VERSION 5.8 ;
BUSBITCHARS "[]" ;
DIVIDERCHAR "/" ;
UNITS
    DATABASE MICRONS 1000 ;
END UNITS

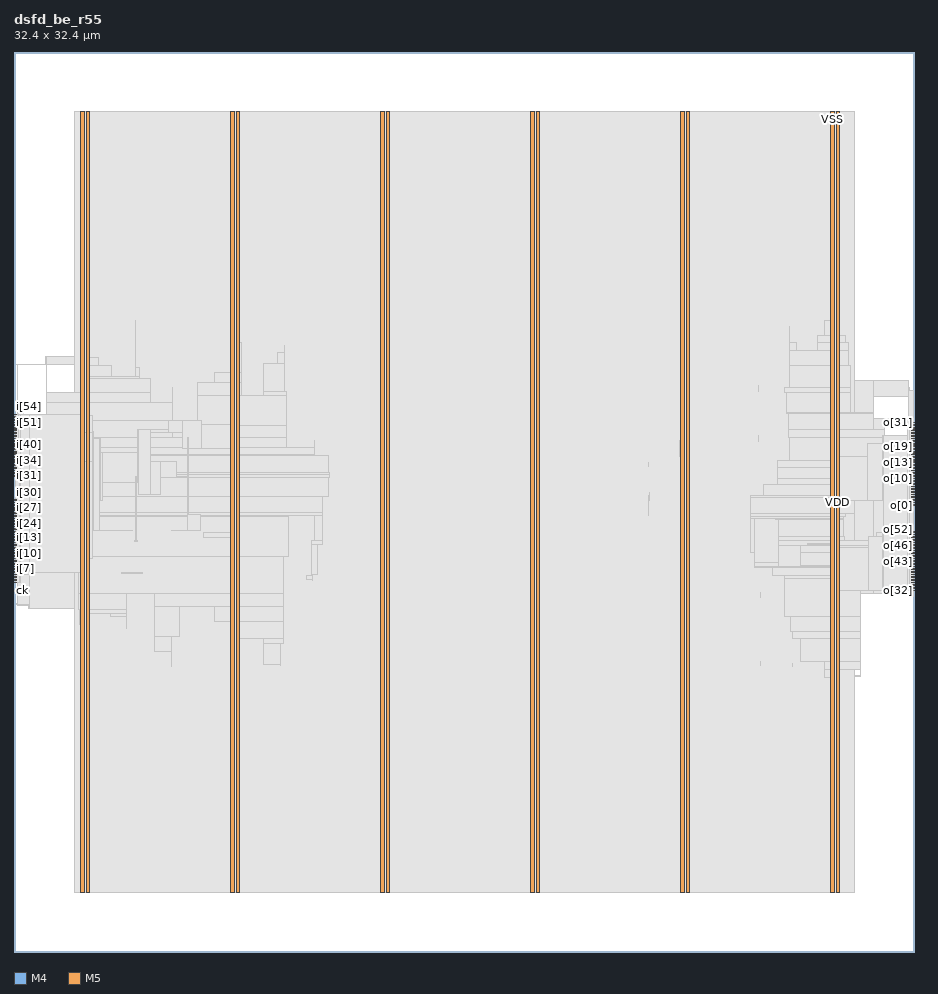
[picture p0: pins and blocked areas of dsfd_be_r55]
MACRO dsfd_be_r55
  FOREIGN dsfd_be_r55 0 0 ;
  CLASS BLOCK ;
  SIZE 32.4 BY 32.4 ;
  PIN ck
    DIRECTION INPUT ;
    USE SIGNAL ;
    PORT
      LAYER M4 ;
        RECT  0 13.296 0.084 13.32 ;
    END
  END ck
  PIN i[0]
    DIRECTION INPUT ;
    USE SIGNAL ;
    PORT
      LAYER M4 ;
        RECT  0 13.392 0.084 13.416 ;
    END
  END i[0]
  PIN i[10]
    DIRECTION INPUT ;
    USE SIGNAL ;
    PORT
      LAYER M4 ;
        RECT  0 14.352 0.084 14.376 ;
    END
  END i[10]
  PIN i[11]
    DIRECTION INPUT ;
    USE SIGNAL ;
    PORT
      LAYER M4 ;
        RECT  0 14.448 0.084 14.472 ;
    END
  END i[11]
  PIN i[12]
    DIRECTION INPUT ;
    USE SIGNAL ;
    PORT
      LAYER M4 ;
        RECT  0 14.544 0.084 14.568 ;
    END
  END i[12]
  PIN i[13]
    DIRECTION INPUT ;
    USE SIGNAL ;
    PORT
      LAYER M4 ;
        RECT  0 14.64 0.084 14.664 ;
    END
  END i[13]
  PIN i[14]
    DIRECTION INPUT ;
    USE SIGNAL ;
    PORT
      LAYER M4 ;
        RECT  0 14.736 0.084 14.76 ;
    END
  END i[14]
  PIN i[15]
    DIRECTION INPUT ;
    USE SIGNAL ;
    PORT
      LAYER M4 ;
        RECT  0 14.832 0.084 14.856 ;
    END
  END i[15]
  PIN i[16]
    DIRECTION INPUT ;
    USE SIGNAL ;
    PORT
      LAYER M4 ;
        RECT  0 14.928 0.084 14.952 ;
    END
  END i[16]
  PIN i[17]
    DIRECTION INPUT ;
    USE SIGNAL ;
    PORT
      LAYER M4 ;
        RECT  0 15.024 0.084 15.048 ;
    END
  END i[17]
  PIN i[18]
    DIRECTION INPUT ;
    USE SIGNAL ;
    PORT
      LAYER M4 ;
        RECT  0 15.12 0.084 15.144 ;
    END
  END i[18]
  PIN i[19]
    DIRECTION INPUT ;
    USE SIGNAL ;
    PORT
      LAYER M4 ;
        RECT  0 15.216 0.084 15.24 ;
    END
  END i[19]
  PIN i[1]
    DIRECTION INPUT ;
    USE SIGNAL ;
    PORT
      LAYER M4 ;
        RECT  0 13.488 0.084 13.512 ;
    END
  END i[1]
  PIN i[20]
    DIRECTION INPUT ;
    USE SIGNAL ;
    PORT
      LAYER M4 ;
        RECT  0 15.312 0.084 15.336 ;
    END
  END i[20]
  PIN i[21]
    DIRECTION INPUT ;
    USE SIGNAL ;
    PORT
      LAYER M4 ;
        RECT  0 15.408 0.084 15.432 ;
    END
  END i[21]
  PIN i[22]
    DIRECTION INPUT ;
    USE SIGNAL ;
    PORT
      LAYER M4 ;
        RECT  0 15.504 0.084 15.528 ;
    END
  END i[22]
  PIN i[23]
    DIRECTION INPUT ;
    USE SIGNAL ;
    PORT
      LAYER M4 ;
        RECT  0 15.6 0.084 15.624 ;
    END
  END i[23]
  PIN i[24]
    DIRECTION INPUT ;
    USE SIGNAL ;
    PORT
      LAYER M4 ;
        RECT  0 15.696 0.084 15.72 ;
    END
  END i[24]
  PIN i[25]
    DIRECTION INPUT ;
    USE SIGNAL ;
    PORT
      LAYER M4 ;
        RECT  0 15.792 0.084 15.816 ;
    END
  END i[25]
  PIN i[26]
    DIRECTION INPUT ;
    USE SIGNAL ;
    PORT
      LAYER M4 ;
        RECT  0 15.888 0.084 15.912 ;
    END
  END i[26]
  PIN i[27]
    DIRECTION INPUT ;
    USE SIGNAL ;
    PORT
      LAYER M4 ;
        RECT  0 15.984 0.084 16.008 ;
    END
  END i[27]
  PIN i[28]
    DIRECTION INPUT ;
    USE SIGNAL ;
    PORT
      LAYER M4 ;
        RECT  0 16.08 0.084 16.104 ;
    END
  END i[28]
  PIN i[29]
    DIRECTION INPUT ;
    USE SIGNAL ;
    PORT
      LAYER M4 ;
        RECT  0 16.176 0.084 16.2 ;
    END
  END i[29]
  PIN i[2]
    DIRECTION INPUT ;
    USE SIGNAL ;
    PORT
      LAYER M4 ;
        RECT  0 13.584 0.084 13.608 ;
    END
  END i[2]
  PIN i[30]
    DIRECTION INPUT ;
    USE SIGNAL ;
    PORT
      LAYER M4 ;
        RECT  0 16.272 0.084 16.296 ;
    END
  END i[30]
  PIN i[31]
    DIRECTION INPUT ;
    USE SIGNAL ;
    PORT
      LAYER M4 ;
        RECT  0 17.136 0.084 17.16 ;
    END
  END i[31]
  PIN i[32]
    DIRECTION INPUT ;
    USE SIGNAL ;
    PORT
      LAYER M4 ;
        RECT  0 17.232 0.084 17.256 ;
    END
  END i[32]
  PIN i[33]
    DIRECTION INPUT ;
    USE SIGNAL ;
    PORT
      LAYER M4 ;
        RECT  0 17.328 0.084 17.352 ;
    END
  END i[33]
  PIN i[34]
    DIRECTION INPUT ;
    USE SIGNAL ;
    PORT
      LAYER M4 ;
        RECT  0 17.424 0.084 17.448 ;
    END
  END i[34]
  PIN i[35]
    DIRECTION INPUT ;
    USE SIGNAL ;
    PORT
      LAYER M4 ;
        RECT  0 17.52 0.084 17.544 ;
    END
  END i[35]
  PIN i[36]
    DIRECTION INPUT ;
    USE SIGNAL ;
    PORT
      LAYER M4 ;
        RECT  0 17.616 0.084 17.64 ;
    END
  END i[36]
  PIN i[37]
    DIRECTION INPUT ;
    USE SIGNAL ;
    PORT
      LAYER M4 ;
        RECT  0 17.712 0.084 17.736 ;
    END
  END i[37]
  PIN i[38]
    DIRECTION INPUT ;
    USE SIGNAL ;
    PORT
      LAYER M4 ;
        RECT  0 17.808 0.084 17.832 ;
    END
  END i[38]
  PIN i[39]
    DIRECTION INPUT ;
    USE SIGNAL ;
    PORT
      LAYER M4 ;
        RECT  0 17.904 0.084 17.928 ;
    END
  END i[39]
  PIN i[3]
    DIRECTION INPUT ;
    USE SIGNAL ;
    PORT
      LAYER M4 ;
        RECT  0 13.68 0.084 13.704 ;
    END
  END i[3]
  PIN i[40]
    DIRECTION INPUT ;
    USE SIGNAL ;
    PORT
      LAYER M4 ;
        RECT  0 18 0.084 18.024 ;
    END
  END i[40]
  PIN i[41]
    DIRECTION INPUT ;
    USE SIGNAL ;
    PORT
      LAYER M4 ;
        RECT  0 18.096 0.084 18.12 ;
    END
  END i[41]
  PIN i[42]
    DIRECTION INPUT ;
    USE SIGNAL ;
    PORT
      LAYER M4 ;
        RECT  0 18.192 0.084 18.216 ;
    END
  END i[42]
  PIN i[43]
    DIRECTION INPUT ;
    USE SIGNAL ;
    PORT
      LAYER M4 ;
        RECT  0 18.288 0.084 18.312 ;
    END
  END i[43]
  PIN i[44]
    DIRECTION INPUT ;
    USE SIGNAL ;
    PORT
      LAYER M4 ;
        RECT  0 18.384 0.084 18.408 ;
    END
  END i[44]
  PIN i[45]
    DIRECTION INPUT ;
    USE SIGNAL ;
    PORT
      LAYER M4 ;
        RECT  0 18.48 0.084 18.504 ;
    END
  END i[45]
  PIN i[46]
    DIRECTION INPUT ;
    USE SIGNAL ;
    PORT
      LAYER M4 ;
        RECT  0 18.576 0.084 18.6 ;
    END
  END i[46]
  PIN i[47]
    DIRECTION INPUT ;
    USE SIGNAL ;
    PORT
      LAYER M4 ;
        RECT  0 18.672 0.084 18.696 ;
    END
  END i[47]
  PIN i[48]
    DIRECTION INPUT ;
    USE SIGNAL ;
    PORT
      LAYER M4 ;
        RECT  0 18.768 0.084 18.792 ;
    END
  END i[48]
  PIN i[49]
    DIRECTION INPUT ;
    USE SIGNAL ;
    PORT
      LAYER M4 ;
        RECT  0 18.864 0.084 18.888 ;
    END
  END i[49]
  PIN i[4]
    DIRECTION INPUT ;
    USE SIGNAL ;
    PORT
      LAYER M4 ;
        RECT  0 13.776 0.084 13.8 ;
    END
  END i[4]
  PIN i[50]
    DIRECTION INPUT ;
    USE SIGNAL ;
    PORT
      LAYER M4 ;
        RECT  0 18.96 0.084 18.984 ;
    END
  END i[50]
  PIN i[51]
    DIRECTION INPUT ;
    USE SIGNAL ;
    PORT
      LAYER M4 ;
        RECT  0 19.056 0.084 19.08 ;
    END
  END i[51]
  PIN i[52]
    DIRECTION INPUT ;
    USE SIGNAL ;
    PORT
      LAYER M4 ;
        RECT  0 19.152 0.084 19.176 ;
    END
  END i[52]
  PIN i[53]
    DIRECTION INPUT ;
    USE SIGNAL ;
    PORT
      LAYER M4 ;
        RECT  0 19.248 0.084 19.272 ;
    END
  END i[53]
  PIN i[54]
    DIRECTION INPUT ;
    USE SIGNAL ;
    PORT
      LAYER M4 ;
        RECT  0 19.344 0.084 19.368 ;
    END
  END i[54]
  PIN i[5]
    DIRECTION INPUT ;
    USE SIGNAL ;
    PORT
      LAYER M4 ;
        RECT  0 13.872 0.084 13.896 ;
    END
  END i[5]
  PIN i[6]
    DIRECTION INPUT ;
    USE SIGNAL ;
    PORT
      LAYER M4 ;
        RECT  0 13.968 0.084 13.992 ;
    END
  END i[6]
  PIN i[7]
    DIRECTION INPUT ;
    USE SIGNAL ;
    PORT
      LAYER M4 ;
        RECT  0 14.064 0.084 14.088 ;
    END
  END i[7]
  PIN i[8]
    DIRECTION INPUT ;
    USE SIGNAL ;
    PORT
      LAYER M4 ;
        RECT  0 14.16 0.084 14.184 ;
    END
  END i[8]
  PIN i[9]
    DIRECTION INPUT ;
    USE SIGNAL ;
    PORT
      LAYER M4 ;
        RECT  0 14.256 0.084 14.28 ;
    END
  END i[9]
  PIN o[0]
    DIRECTION OUTPUT ;
    USE SIGNAL ;
    PORT
      LAYER M4 ;
        RECT  32.316 16.08 32.4 16.104 ;
    END
  END o[0]
  PIN o[10]
    DIRECTION OUTPUT ;
    USE SIGNAL ;
    PORT
      LAYER M4 ;
        RECT  32.316 17.04 32.4 17.064 ;
    END
  END o[10]
  PIN o[11]
    DIRECTION OUTPUT ;
    USE SIGNAL ;
    PORT
      LAYER M4 ;
        RECT  32.316 17.136 32.4 17.16 ;
    END
  END o[11]
  PIN o[12]
    DIRECTION OUTPUT ;
    USE SIGNAL ;
    PORT
      LAYER M4 ;
        RECT  32.316 17.232 32.4 17.256 ;
    END
  END o[12]
  PIN o[13]
    DIRECTION OUTPUT ;
    USE SIGNAL ;
    PORT
      LAYER M4 ;
        RECT  32.316 17.328 32.4 17.352 ;
    END
  END o[13]
  PIN o[14]
    DIRECTION OUTPUT ;
    USE SIGNAL ;
    PORT
      LAYER M4 ;
        RECT  32.316 17.424 32.4 17.448 ;
    END
  END o[14]
  PIN o[15]
    DIRECTION OUTPUT ;
    USE SIGNAL ;
    PORT
      LAYER M4 ;
        RECT  32.316 17.52 32.4 17.544 ;
    END
  END o[15]
  PIN o[16]
    DIRECTION OUTPUT ;
    USE SIGNAL ;
    PORT
      LAYER M4 ;
        RECT  32.316 17.616 32.4 17.64 ;
    END
  END o[16]
  PIN o[17]
    DIRECTION OUTPUT ;
    USE SIGNAL ;
    PORT
      LAYER M4 ;
        RECT  32.316 17.712 32.4 17.736 ;
    END
  END o[17]
  PIN o[18]
    DIRECTION OUTPUT ;
    USE SIGNAL ;
    PORT
      LAYER M4 ;
        RECT  32.316 17.808 32.4 17.832 ;
    END
  END o[18]
  PIN o[19]
    DIRECTION OUTPUT ;
    USE SIGNAL ;
    PORT
      LAYER M4 ;
        RECT  32.316 17.904 32.4 17.928 ;
    END
  END o[19]
  PIN o[1]
    DIRECTION OUTPUT ;
    USE SIGNAL ;
    PORT
      LAYER M4 ;
        RECT  32.316 16.176 32.4 16.2 ;
    END
  END o[1]
  PIN o[20]
    DIRECTION OUTPUT ;
    USE SIGNAL ;
    PORT
      LAYER M4 ;
        RECT  32.316 18 32.4 18.024 ;
    END
  END o[20]
  PIN o[21]
    DIRECTION OUTPUT ;
    USE SIGNAL ;
    PORT
      LAYER M4 ;
        RECT  32.316 18.096 32.4 18.12 ;
    END
  END o[21]
  PIN o[22]
    DIRECTION OUTPUT ;
    USE SIGNAL ;
    PORT
      LAYER M4 ;
        RECT  32.316 18.192 32.4 18.216 ;
    END
  END o[22]
  PIN o[23]
    DIRECTION OUTPUT ;
    USE SIGNAL ;
    PORT
      LAYER M4 ;
        RECT  32.316 18.288 32.4 18.312 ;
    END
  END o[23]
  PIN o[24]
    DIRECTION OUTPUT ;
    USE SIGNAL ;
    PORT
      LAYER M4 ;
        RECT  32.316 18.384 32.4 18.408 ;
    END
  END o[24]
  PIN o[25]
    DIRECTION OUTPUT ;
    USE SIGNAL ;
    PORT
      LAYER M4 ;
        RECT  32.316 18.48 32.4 18.504 ;
    END
  END o[25]
  PIN o[26]
    DIRECTION OUTPUT ;
    USE SIGNAL ;
    PORT
      LAYER M4 ;
        RECT  32.316 18.576 32.4 18.6 ;
    END
  END o[26]
  PIN o[27]
    DIRECTION OUTPUT ;
    USE SIGNAL ;
    PORT
      LAYER M4 ;
        RECT  32.316 18.672 32.4 18.696 ;
    END
  END o[27]
  PIN o[28]
    DIRECTION OUTPUT ;
    USE SIGNAL ;
    PORT
      LAYER M4 ;
        RECT  32.316 18.768 32.4 18.792 ;
    END
  END o[28]
  PIN o[29]
    DIRECTION OUTPUT ;
    USE SIGNAL ;
    PORT
      LAYER M4 ;
        RECT  32.316 18.864 32.4 18.888 ;
    END
  END o[29]
  PIN o[2]
    DIRECTION OUTPUT ;
    USE SIGNAL ;
    PORT
      LAYER M4 ;
        RECT  32.316 16.272 32.4 16.296 ;
    END
  END o[2]
  PIN o[30]
    DIRECTION OUTPUT ;
    USE SIGNAL ;
    PORT
      LAYER M4 ;
        RECT  32.316 18.96 32.4 18.984 ;
    END
  END o[30]
  PIN o[31]
    DIRECTION OUTPUT ;
    USE SIGNAL ;
    PORT
      LAYER M4 ;
        RECT  32.316 19.056 32.4 19.08 ;
    END
  END o[31]
  PIN o[32]
    DIRECTION OUTPUT ;
    USE SIGNAL ;
    PORT
      LAYER M4 ;
        RECT  32.316 13.008 32.4 13.032 ;
    END
  END o[32]
  PIN o[33]
    DIRECTION OUTPUT ;
    USE SIGNAL ;
    PORT
      LAYER M4 ;
        RECT  32.316 13.104 32.4 13.128 ;
    END
  END o[33]
  PIN o[34]
    DIRECTION OUTPUT ;
    USE SIGNAL ;
    PORT
      LAYER M4 ;
        RECT  32.316 13.2 32.4 13.224 ;
    END
  END o[34]
  PIN o[35]
    DIRECTION OUTPUT ;
    USE SIGNAL ;
    PORT
      LAYER M4 ;
        RECT  32.316 13.296 32.4 13.32 ;
    END
  END o[35]
  PIN o[36]
    DIRECTION OUTPUT ;
    USE SIGNAL ;
    PORT
      LAYER M4 ;
        RECT  32.316 13.392 32.4 13.416 ;
    END
  END o[36]
  PIN o[37]
    DIRECTION OUTPUT ;
    USE SIGNAL ;
    PORT
      LAYER M4 ;
        RECT  32.316 13.488 32.4 13.512 ;
    END
  END o[37]
  PIN o[38]
    DIRECTION OUTPUT ;
    USE SIGNAL ;
    PORT
      LAYER M4 ;
        RECT  32.316 13.584 32.4 13.608 ;
    END
  END o[38]
  PIN o[39]
    DIRECTION OUTPUT ;
    USE SIGNAL ;
    PORT
      LAYER M4 ;
        RECT  32.316 13.68 32.4 13.704 ;
    END
  END o[39]
  PIN o[3]
    DIRECTION OUTPUT ;
    USE SIGNAL ;
    PORT
      LAYER M4 ;
        RECT  32.316 16.368 32.4 16.392 ;
    END
  END o[3]
  PIN o[40]
    DIRECTION OUTPUT ;
    USE SIGNAL ;
    PORT
      LAYER M4 ;
        RECT  32.316 13.776 32.4 13.8 ;
    END
  END o[40]
  PIN o[41]
    DIRECTION OUTPUT ;
    USE SIGNAL ;
    PORT
      LAYER M4 ;
        RECT  32.316 13.872 32.4 13.896 ;
    END
  END o[41]
  PIN o[42]
    DIRECTION OUTPUT ;
    USE SIGNAL ;
    PORT
      LAYER M4 ;
        RECT  32.316 13.968 32.4 13.992 ;
    END
  END o[42]
  PIN o[43]
    DIRECTION OUTPUT ;
    USE SIGNAL ;
    PORT
      LAYER M4 ;
        RECT  32.316 14.064 32.4 14.088 ;
    END
  END o[43]
  PIN o[44]
    DIRECTION OUTPUT ;
    USE SIGNAL ;
    PORT
      LAYER M4 ;
        RECT  32.316 14.16 32.4 14.184 ;
    END
  END o[44]
  PIN o[45]
    DIRECTION OUTPUT ;
    USE SIGNAL ;
    PORT
      LAYER M4 ;
        RECT  32.316 14.256 32.4 14.28 ;
    END
  END o[45]
  PIN o[46]
    DIRECTION OUTPUT ;
    USE SIGNAL ;
    PORT
      LAYER M4 ;
        RECT  32.316 14.352 32.4 14.376 ;
    END
  END o[46]
  PIN o[47]
    DIRECTION OUTPUT ;
    USE SIGNAL ;
    PORT
      LAYER M4 ;
        RECT  32.316 14.448 32.4 14.472 ;
    END
  END o[47]
  PIN o[48]
    DIRECTION OUTPUT ;
    USE SIGNAL ;
    PORT
      LAYER M4 ;
        RECT  32.316 14.544 32.4 14.568 ;
    END
  END o[48]
  PIN o[49]
    DIRECTION OUTPUT ;
    USE SIGNAL ;
    PORT
      LAYER M4 ;
        RECT  32.316 14.64 32.4 14.664 ;
    END
  END o[49]
  PIN o[4]
    DIRECTION OUTPUT ;
    USE SIGNAL ;
    PORT
      LAYER M4 ;
        RECT  32.316 16.464 32.4 16.488 ;
    END
  END o[4]
  PIN o[50]
    DIRECTION OUTPUT ;
    USE SIGNAL ;
    PORT
      LAYER M4 ;
        RECT  32.316 14.736 32.4 14.76 ;
    END
  END o[50]
  PIN o[51]
    DIRECTION OUTPUT ;
    USE SIGNAL ;
    PORT
      LAYER M4 ;
        RECT  32.316 14.832 32.4 14.856 ;
    END
  END o[51]
  PIN o[52]
    DIRECTION OUTPUT ;
    USE SIGNAL ;
    PORT
      LAYER M4 ;
        RECT  32.316 14.928 32.4 14.952 ;
    END
  END o[52]
  PIN o[53]
    DIRECTION OUTPUT ;
    USE SIGNAL ;
    PORT
      LAYER M4 ;
        RECT  32.316 15.024 32.4 15.048 ;
    END
  END o[53]
  PIN o[54]
    DIRECTION OUTPUT ;
    USE SIGNAL ;
    PORT
      LAYER M4 ;
        RECT  32.316 15.12 32.4 15.144 ;
    END
  END o[54]
  PIN o[5]
    DIRECTION OUTPUT ;
    USE SIGNAL ;
    PORT
      LAYER M4 ;
        RECT  32.316 16.56 32.4 16.584 ;
    END
  END o[5]
  PIN o[6]
    DIRECTION OUTPUT ;
    USE SIGNAL ;
    PORT
      LAYER M4 ;
        RECT  32.316 16.656 32.4 16.68 ;
    END
  END o[6]
  PIN o[7]
    DIRECTION OUTPUT ;
    USE SIGNAL ;
    PORT
      LAYER M4 ;
        RECT  32.316 16.752 32.4 16.776 ;
    END
  END o[7]
  PIN o[8]
    DIRECTION OUTPUT ;
    USE SIGNAL ;
    PORT
      LAYER M4 ;
        RECT  32.316 16.848 32.4 16.872 ;
    END
  END o[8]
  PIN o[9]
    DIRECTION OUTPUT ;
    USE SIGNAL ;
    PORT
      LAYER M4 ;
        RECT  32.316 16.944 32.4 16.968 ;
    END
  END o[9]
  PIN VDD
    DIRECTION INOUT ;
    USE POWER ;
    PORT
      LAYER M5 ;
        RECT  29.592 2.151 29.712 30.249 ;
        RECT  24.192 2.151 24.312 30.249 ;
        RECT  18.792 2.151 18.912 30.249 ;
        RECT  13.392 2.151 13.512 30.249 ;
        RECT  7.992 2.151 8.112 30.249 ;
        RECT  2.592 2.151 2.712 30.249 ;
    END
  END VDD
  PIN VSS
    DIRECTION INOUT ;
    USE GROUND ;
    PORT
      LAYER M5 ;
        RECT  29.4 2.137 29.52 30.263 ;
        RECT  24 2.137 24.12 30.263 ;
        RECT  18.6 2.137 18.72 30.263 ;
        RECT  13.2 2.137 13.32 30.263 ;
        RECT  7.8 2.137 7.92 30.263 ;
        RECT  2.4 2.137 2.52 30.263 ;
    END
  END VSS
  # OT_OBS_CLOSED layer=M5 d_um=1.536 added=0
  OBS
    LAYER RVTN ;
     RECT  2.16 2.16 30.24 2.295 ;
     RECT  2.16 2.565 30.24 2.835 ;
     RECT  2.16 3.105 30.24 3.375 ;
     RECT  2.16 3.645 30.24 3.915 ;
     RECT  2.16 4.185 30.24 4.455 ;
     RECT  2.16 4.725 30.24 4.995 ;
     RECT  2.16 5.265 30.24 5.535 ;
     RECT  2.16 5.805 30.24 6.075 ;
     RECT  2.16 6.345 30.24 6.615 ;
     RECT  2.16 6.885 30.24 7.155 ;
     RECT  2.16 7.425 30.24 7.695 ;
     RECT  2.16 7.965 30.24 8.235 ;
     RECT  2.16 8.505 30.24 8.775 ;
     RECT  2.16 9.045 30.24 9.315 ;
     RECT  2.16 9.585 30.24 9.855 ;
     RECT  2.16 10.125 30.24 10.395 ;
     RECT  2.16 10.665 30.24 10.935 ;
     RECT  2.16 11.205 30.24 11.475 ;
     RECT  2.16 11.745 30.24 12.015 ;
     RECT  2.16 12.285 30.24 12.555 ;
     RECT  2.16 12.825 30.24 13.095 ;
     RECT  2.16 13.365 30.24 13.635 ;
     RECT  2.16 13.905 30.24 14.175 ;
     RECT  2.16 14.445 30.24 14.715 ;
     RECT  2.16 14.985 30.24 15.255 ;
     RECT  2.16 15.525 30.24 15.795 ;
     RECT  2.16 16.065 30.24 16.335 ;
     RECT  2.16 16.605 30.24 16.875 ;
     RECT  2.16 17.145 30.24 17.415 ;
     RECT  2.16 17.685 30.24 17.955 ;
     RECT  2.16 18.225 30.24 18.495 ;
     RECT  2.16 18.765 30.24 19.035 ;
     RECT  2.16 19.305 30.24 19.575 ;
     RECT  2.16 19.845 30.24 20.115 ;
     RECT  2.16 20.385 30.24 20.655 ;
     RECT  2.16 20.925 30.24 21.195 ;
     RECT  2.16 21.465 30.24 21.735 ;
     RECT  2.16 22.005 30.24 22.275 ;
     RECT  2.16 22.545 30.24 22.815 ;
     RECT  2.16 23.085 30.24 23.355 ;
     RECT  2.16 23.625 30.24 23.895 ;
     RECT  2.16 24.165 30.24 24.435 ;
     RECT  2.16 24.705 30.24 24.975 ;
     RECT  2.16 25.245 30.24 25.515 ;
     RECT  2.16 25.785 30.24 26.055 ;
     RECT  2.16 26.325 30.24 26.595 ;
     RECT  2.16 26.865 30.24 27.135 ;
     RECT  2.16 27.405 30.24 27.675 ;
     RECT  2.16 27.945 30.24 28.215 ;
     RECT  2.16 28.485 30.24 28.755 ;
     RECT  2.16 29.025 30.24 29.295 ;
     RECT  2.16 29.565 30.24 29.835 ;
     RECT  2.16 30.105 30.24 30.24 ;
    LAYER RVTP ;
     RECT  2.16 2.295 30.24 2.565 ;
     RECT  2.16 2.835 30.24 3.105 ;
     RECT  2.16 3.375 30.24 3.645 ;
     RECT  2.16 3.915 30.24 4.185 ;
     RECT  2.16 4.455 30.24 4.725 ;
     RECT  2.16 4.995 30.24 5.265 ;
     RECT  2.16 5.535 30.24 5.805 ;
     RECT  2.16 6.075 30.24 6.345 ;
     RECT  2.16 6.615 30.24 6.885 ;
     RECT  2.16 7.155 30.24 7.425 ;
     RECT  2.16 7.695 30.24 7.965 ;
     RECT  2.16 8.235 30.24 8.505 ;
     RECT  2.16 8.775 30.24 9.045 ;
     RECT  2.16 9.315 30.24 9.585 ;
     RECT  2.16 9.855 30.24 10.125 ;
     RECT  2.16 10.395 30.24 10.665 ;
     RECT  2.16 10.935 30.24 11.205 ;
     RECT  2.16 11.475 30.24 11.745 ;
     RECT  2.16 12.015 30.24 12.285 ;
     RECT  2.16 12.555 30.24 12.825 ;
     RECT  2.16 13.095 30.24 13.365 ;
     RECT  2.16 13.635 30.24 13.905 ;
     RECT  2.16 14.175 30.24 14.445 ;
     RECT  2.16 14.715 30.24 14.985 ;
     RECT  2.16 15.255 30.24 15.525 ;
     RECT  2.16 15.795 30.24 16.065 ;
     RECT  2.16 16.335 30.24 16.605 ;
     RECT  2.16 16.875 30.24 17.145 ;
     RECT  2.16 17.415 30.24 17.685 ;
     RECT  2.16 17.955 30.24 18.225 ;
     RECT  2.16 18.495 30.24 18.765 ;
     RECT  2.16 19.035 30.24 19.305 ;
     RECT  2.16 19.575 30.24 19.845 ;
     RECT  2.16 20.115 30.24 20.385 ;
     RECT  2.16 20.655 30.24 20.925 ;
     RECT  2.16 21.195 30.24 21.465 ;
     RECT  2.16 21.735 30.24 22.005 ;
     RECT  2.16 22.275 30.24 22.545 ;
     RECT  2.16 22.815 30.24 23.085 ;
     RECT  2.16 23.355 30.24 23.625 ;
     RECT  2.16 23.895 30.24 24.165 ;
     RECT  2.16 24.435 30.24 24.705 ;
     RECT  2.16 24.975 30.24 25.245 ;
     RECT  2.16 25.515 30.24 25.785 ;
     RECT  2.16 26.055 30.24 26.325 ;
     RECT  2.16 26.595 30.24 26.865 ;
     RECT  2.16 27.135 30.24 27.405 ;
     RECT  2.16 27.675 30.24 27.945 ;
     RECT  2.16 28.215 30.24 28.485 ;
     RECT  2.16 28.755 30.24 29.025 ;
     RECT  2.16 29.295 30.24 29.565 ;
     RECT  2.16 29.835 30.24 30.105 ;
    LAYER M1 ;
     RECT  2.16 2.151 30.24 30.249 ;
    LAYER M2 ;
     RECT  0.103 12.528 0.139 12.546 ;
     RECT  0.103 13.572 0.139 13.59 ;
     RECT  0.139 12.492 0.175 12.546 ;
     RECT  0.139 13.572 0.175 13.662 ;
     RECT  0.103 14.571 0.175 14.778 ;
     RECT  0.175 12.492 0.535 14.778 ;
     RECT  0.103 21.132 1.147 21.15 ;
     RECT  0.535 12.366 2.16 14.778 ;
     RECT  0.175 16.11 2.16 16.128 ;
     RECT  0.535 16.956 2.16 16.974 ;
     RECT  1.687 20.124 2.16 20.142 ;
     RECT  1.147 21.132 2.16 21.42 ;
     RECT  2.16 2.151 30.24 30.249 ;
     RECT  30.24 9.936 30.479 9.954 ;
     RECT  30.24 12.906 30.947 20.574 ;
     RECT  30.947 12.906 31.343 19.224 ;
     RECT  31.343 12.906 31.379 13.932 ;
     RECT  31.343 15.876 31.379 15.894 ;
     RECT  31.379 13.914 31.415 13.932 ;
     RECT  30.947 20.016 32.207 20.574 ;
     RECT  32.207 20.016 32.243 20.304 ;
     RECT  31.343 18.936 32.279 19.224 ;
     RECT  31.343 14.724 32.315 14.742 ;
     RECT  31.343 16.848 32.315 17.514 ;
     RECT  32.243 20.016 32.315 20.214 ;
     RECT  32.287 18.396 32.387 18.414 ;
     RECT  32.315 20.196 32.387 20.214 ;
    LAYER M3 ;
     RECT  2.415 2.143 2.505 2.413 ;
     RECT  7.815 2.143 7.905 2.413 ;
     RECT  13.215 2.143 13.305 2.413 ;
     RECT  18.615 2.143 18.705 2.413 ;
     RECT  24.015 2.143 24.105 2.413 ;
     RECT  29.415 2.143 29.505 2.413 ;
     RECT  29.415 2.413 29.697 9.895 ;
     RECT  29.16 9.895 29.697 10.165 ;
     RECT  30.456 9.931 30.474 10.165 ;
     RECT  9.576 10.327 9.594 10.363 ;
     RECT  28.008 10.291 28.026 10.391 ;
     RECT  26.856 10.327 26.874 10.463 ;
     RECT  29.16 10.165 30.474 10.471 ;
     RECT  5.652 10.291 5.67 10.831 ;
     RECT  8.964 10.363 9.594 11.101 ;
     RECT  7.815 2.413 8.097 11.281 ;
     RECT  8.964 11.101 9.702 11.281 ;
     RECT  28.296 10.471 30.474 11.281 ;
     RECT  5.04 10.831 5.67 11.371 ;
     RECT  28.008 11.281 30.474 11.551 ;
     RECT  2.415 2.413 2.697 11.785 ;
     RECT  7.815 11.281 9.702 11.911 ;
     RECT  4.032 11.641 4.05 12.091 ;
     RECT  27.936 11.551 30.474 12.091 ;
     RECT  2.34 11.785 2.697 12.181 ;
     RECT  3.456 12.091 4.05 12.181 ;
     RECT  2.34 12.181 4.05 12.325 ;
     RECT  5.04 11.371 5.958 12.451 ;
     RECT  7.2 11.911 9.702 12.451 ;
     RECT  0.54 12.361 0.558 12.487 ;
     RECT  0.144 12.487 0.558 12.523 ;
     RECT  2.304 12.325 4.05 12.901 ;
     RECT  5.04 12.451 9.702 12.901 ;
     RECT  26.856 12.757 26.874 12.929 ;
     RECT  10.728 13.369 10.746 13.405 ;
     RECT  27.72 12.091 30.474 13.441 ;
     RECT  31.356 12.901 31.374 13.441 ;
     RECT  10.512 13.405 10.746 13.559 ;
     RECT  27.72 13.441 31.374 13.567 ;
     RECT  10.692 13.559 10.746 13.603 ;
     RECT  0.108 12.523 0.558 13.613 ;
     RECT  27.288 13.567 31.374 13.837 ;
     RECT  26.64 13.837 31.374 13.865 ;
     RECT  28.296 13.865 31.374 13.9 ;
     RECT  26.64 13.865 27.522 14.009 ;
     RECT  2.304 12.901 9.702 14.251 ;
     RECT  26.64 14.009 26.658 14.377 ;
     RECT  28.296 13.9 31.41 14.381 ;
     RECT  27.504 14.009 27.522 14.647 ;
     RECT  28.296 14.381 31.338 14.647 ;
     RECT  0.108 13.613 0.342 14.669 ;
     RECT  10.692 13.603 10.926 14.683 ;
     RECT  10.692 14.683 11.106 14.819 ;
     RECT  27.504 14.647 31.338 14.819 ;
     RECT  32.292 14.719 32.31 14.861 ;
     RECT  27.504 14.819 29.898 14.945 ;
     RECT  0.108 14.669 0.306 14.957 ;
     RECT  30.78 14.819 31.338 14.957 ;
     RECT  31.032 14.957 31.338 15.089 ;
     RECT  31.284 15.089 31.338 15.179 ;
     RECT  0.144 14.957 0.306 15.341 ;
     RECT  27.504 14.945 29.862 15.565 ;
     RECT  26.496 14.377 26.658 15.601 ;
     RECT  27.396 15.565 29.862 15.601 ;
     RECT  2.304 14.251 9.882 15.691 ;
     RECT  26.496 15.601 29.862 15.691 ;
     RECT  2.268 15.691 9.882 15.727 ;
     RECT  10.8 14.819 11.106 15.727 ;
     RECT  26.496 15.691 29.934 15.799 ;
     RECT  2.268 15.727 11.106 15.827 ;
     RECT  31.32 15.179 31.338 15.871 ;
     RECT  0.144 15.341 0.162 16.105 ;
     RECT  0.144 16.105 0.198 16.171 ;
     RECT  31.32 15.871 31.374 16.205 ;
     RECT  0.144 16.171 0.342 16.267 ;
     RECT  22.824 15.727 22.842 16.267 ;
     RECT  26.496 15.799 30.258 16.363 ;
     RECT  31.32 16.205 31.338 16.363 ;
     RECT  0.108 16.267 0.342 16.397 ;
     RECT  2.304 15.827 11.106 16.411 ;
     RECT  22.824 16.267 22.878 16.439 ;
     RECT  26.496 16.363 31.338 16.439 ;
     RECT  22.86 16.439 22.878 16.529 ;
     RECT  26.964 16.439 31.338 16.835 ;
     RECT  0.18 16.397 0.342 16.951 ;
     RECT  27.468 16.835 31.338 17.041 ;
     RECT  2.304 16.411 11.322 17.077 ;
     RECT  0.18 16.951 0.558 17.165 ;
     RECT  2.304 17.077 11.358 17.185 ;
     RECT  2.268 17.185 11.358 17.249 ;
     RECT  0.54 17.165 0.558 17.261 ;
     RECT  27.468 17.041 31.374 17.453 ;
     RECT  32.292 16.747 32.31 17.519 ;
     RECT  22.824 17.491 22.842 17.609 ;
     RECT  27.468 17.453 31.338 17.681 ;
     RECT  24.015 2.413 24.297 17.851 ;
     RECT  2.268 17.249 11.322 17.879 ;
     RECT  2.268 17.879 10.818 17.899 ;
     RECT  1.692 17.899 10.818 18.149 ;
     RECT  0.432 18.283 0.45 18.379 ;
     RECT  32.292 18.379 32.31 18.391 ;
     RECT  10.8 18.149 10.818 18.419 ;
     RECT  23.94 17.851 24.297 18.419 ;
     RECT  0.36 18.379 0.45 18.461 ;
     RECT  0.36 18.461 0.378 18.509 ;
     RECT  1.692 18.149 9.81 18.527 ;
     RECT  27.9 17.681 31.338 18.535 ;
     RECT  26.784 18.391 26.802 18.599 ;
     RECT  32.292 18.391 32.382 18.763 ;
     RECT  27.864 18.535 31.338 18.797 ;
     RECT  32.256 18.763 32.382 18.859 ;
     RECT  32.22 18.859 32.382 18.955 ;
     RECT  6.552 18.527 9.81 18.959 ;
     RECT  1.692 18.527 5.706 19.147 ;
     RECT  0.108 18.763 0.342 19.373 ;
     RECT  27.864 18.797 30.942 19.381 ;
     RECT  27.792 19.381 30.942 19.409 ;
     RECT  30.924 19.409 30.942 19.679 ;
     RECT  1.152 19.147 5.706 19.769 ;
     RECT  6.588 18.959 9.81 20.039 ;
     RECT  1.152 19.769 4.914 20.147 ;
     RECT  27.792 19.409 30.114 20.155 ;
     RECT  8.964 20.039 9.81 20.183 ;
     RECT  32.184 18.955 32.382 20.219 ;
     RECT  5.688 19.769 5.706 20.309 ;
     RECT  27.72 20.155 30.114 20.309 ;
     RECT  32.184 20.219 32.238 20.309 ;
     RECT  26.784 20.191 26.802 20.381 ;
     RECT  6.588 20.039 8.19 20.489 ;
     RECT  32.184 20.309 32.202 20.579 ;
     RECT  2.415 20.147 4.914 20.651 ;
     RECT  2.415 20.651 4.518 20.723 ;
     RECT  7.2 20.489 8.19 20.849 ;
     RECT  4.356 20.723 4.518 21.029 ;
     RECT  2.415 20.723 3.51 21.119 ;
     RECT  27.9 20.309 30.114 21.119 ;
     RECT  0.108 19.373 0.126 21.155 ;
     RECT  8.964 20.183 9.738 21.191 ;
     RECT  2.415 21.119 3.042 21.389 ;
     RECT  1.152 20.147 1.17 21.425 ;
     RECT  9.468 21.191 9.738 21.569 ;
     RECT  27.9 21.119 30.042 21.659 ;
     RECT  9.72 21.569 9.738 21.839 ;
     RECT  7.815 20.849 8.19 21.929 ;
     RECT  27.9 21.659 28.17 21.929 ;
     RECT  28.908 21.659 30.042 21.929 ;
     RECT  28.908 21.929 29.934 22.199 ;
     RECT  27.9 21.929 27.918 22.505 ;
     RECT  4.356 21.029 4.374 22.739 ;
     RECT  29.16 22.199 29.697 22.739 ;
     RECT  2.415 21.389 2.697 29.987 ;
     RECT  7.815 21.929 8.097 29.987 ;
     RECT  13.215 2.413 13.497 29.987 ;
     RECT  18.615 2.413 18.897 29.987 ;
     RECT  24.015 18.419 24.297 29.987 ;
     RECT  29.415 22.739 29.697 29.987 ;
     RECT  2.415 29.987 2.505 30.257 ;
     RECT  7.815 29.987 7.905 30.257 ;
     RECT  13.215 29.987 13.305 30.257 ;
     RECT  18.615 29.987 18.705 30.257 ;
     RECT  24.015 29.987 24.105 30.257 ;
     RECT  29.415 29.987 29.505 30.257 ;
    LAYER M4 ;
     RECT  0.06 13.296 0.227 19.368 ;
     RECT  0.227 13.584 0.569 19.368 ;
     RECT  0.569 13.68 2.408 19.368 ;
     RECT  2.408 2.148 2.512 30.252 ;
     RECT  2.512 2.418 2.704 29.982 ;
     RECT  2.704 14.16 2.837 19.32 ;
     RECT  2.837 15.168 2.873 18.744 ;
     RECT  2.873 15.168 3.089 18.504 ;
     RECT  3.089 16.272 3.125 18.504 ;
     RECT  3.125 16.272 3.197 17.976 ;
     RECT  3.089 15.168 4.277 15.192 ;
     RECT  4.345 14.784 4.429 14.808 ;
     RECT  3.197 16.896 4.453 17.976 ;
     RECT  4.453 16.896 4.489 18.792 ;
     RECT  3.877 13.632 4.637 13.656 ;
     RECT  4.489 16.464 4.925 18.792 ;
     RECT  4.925 16.464 5.285 17.64 ;
     RECT  4.925 18.72 5.569 18.792 ;
     RECT  5.285 17.088 5.861 17.64 ;
     RECT  5.569 18.72 6.073 19.128 ;
     RECT  5.677 15.168 6.229 15.192 ;
     RECT  5.861 17.088 6.275 17.112 ;
     RECT  6.229 15.168 6.725 15.768 ;
     RECT  6.073 18.144 6.761 19.128 ;
     RECT  6.829 14.928 7.808 15.096 ;
     RECT  6.761 18.144 7.808 18.984 ;
     RECT  7.808 2.148 7.912 30.252 ;
     RECT  7.912 2.418 8.104 29.982 ;
     RECT  13.208 2.148 13.312 30.252 ;
     RECT  13.312 2.418 13.504 29.982 ;
     RECT  18.608 2.148 18.712 30.252 ;
     RECT  18.712 2.418 18.904 29.982 ;
     RECT  24.008 2.148 24.112 30.252 ;
     RECT  24.112 2.418 24.304 29.982 ;
     RECT  28.573 14.688 29.408 14.712 ;
     RECT  29.408 2.148 29.512 30.252 ;
     RECT  29.512 2.418 29.704 29.982 ;
     RECT  29.704 16.272 30.733 17.832 ;
     RECT  29.704 13.008 30.769 14.568 ;
     RECT  30.769 13.008 31.273 14.952 ;
     RECT  30.733 16.272 31.273 18.312 ;
     RECT  31.273 13.008 31.309 15.144 ;
     RECT  31.273 16.272 31.309 18.6 ;
     RECT  31.309 13.008 32.173 18.6 ;
     RECT  32.173 13.008 32.245 18.984 ;
     RECT  32.245 13.008 32.364 19.08 ;
    LAYER M5 ;
     RECT  2.4 2.137 2.52 2.151 ;
     RECT  7.8 2.137 7.92 2.151 ;
     RECT  13.2 2.137 13.32 2.151 ;
     RECT  18.6 2.137 18.72 2.151 ;
     RECT  24 2.137 24.12 2.151 ;
     RECT  29.4 2.137 29.52 2.151 ;
     RECT  0.192 13.285 0.216 16.931 ;
     RECT  4.368 14.773 4.392 17.123 ;
     RECT  2.4 2.151 2.712 17.653 ;
     RECT  6.24 15.733 6.264 18.515 ;
     RECT  2.4 17.653 2.808 18.707 ;
     RECT  0.144 18.469 0.168 19.379 ;
     RECT  2.4 18.707 2.712 30.249 ;
     RECT  7.8 2.151 8.112 30.249 ;
     RECT  13.2 2.151 13.512 30.249 ;
     RECT  18.6 2.151 18.912 30.249 ;
     RECT  24 2.151 24.312 30.249 ;
     RECT  29.4 2.151 29.712 30.249 ;
     RECT  2.4 30.249 2.52 30.263 ;
     RECT  7.8 30.249 7.92 30.263 ;
     RECT  13.2 30.249 13.32 30.263 ;
     RECT  18.6 30.249 18.72 30.263 ;
     RECT  24 30.249 24.12 30.263 ;
     RECT  29.4 30.249 29.52 30.263 ;
  END
END dsfd_be_r55
END LIBRARY
